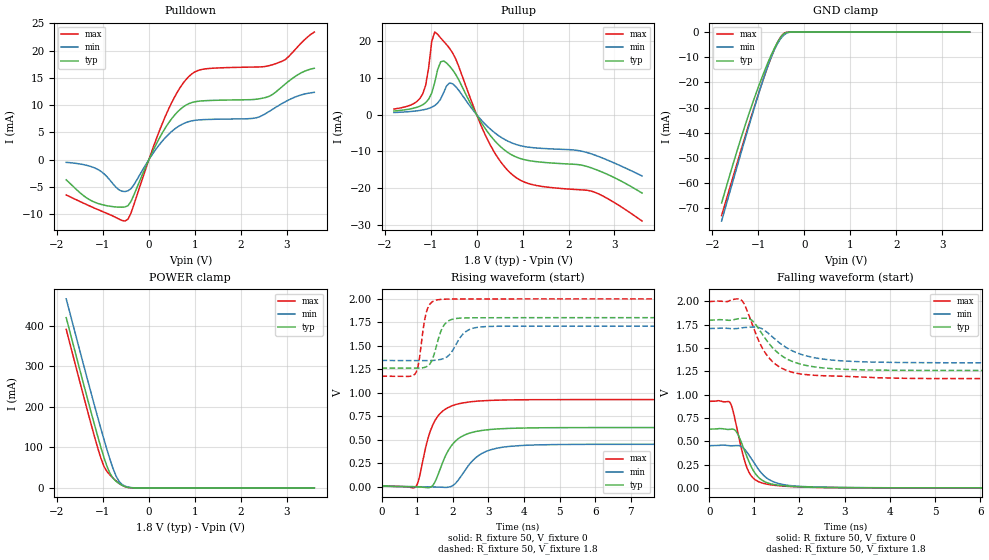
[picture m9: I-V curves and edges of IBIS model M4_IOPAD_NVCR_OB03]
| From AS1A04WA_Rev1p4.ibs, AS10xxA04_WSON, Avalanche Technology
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[Model] M4_IOPAD_NVCR_OB03
Model_type I/O
Enable   Active-High
Vinl  =  0.54
Vinh  =  1.26
Vmeas =  0.9
Cref  =  30e-12
| Capacitance  typ   min   max
C_comp   3.869840e-12   3.575244e-12   4.229518e-12
| Variables   typ   min   max
[GND Clamp Reference]   0   0   0
[POWER Clamp Reference]   1.8   1.71   2
[Pulldown Reference]   0   0   0
[Pullup Reference]   1.8   1.71   2
[Temperature Range]   25   125   -40
[Voltage Range]   1.8   1.71   2
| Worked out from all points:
|   slope of the pulldown table from 0 to 0.27 V, typ, clamps not added: 59.1 ohm
|   slope of the pullup table from 0 to 0.27 V, typ, clamps not added: 51.8 ohm
|   GND clamp passes 1 mA (typ) near -0.46 V on its own axis
|   POWER clamp passes 1 mA (typ) near -0.44 V on its own axis
|   falling waveform, R_fixture 50, V_fixture 0: 20-80 % time 366ps typ, 451ps min, 295ps max; typ from 0.63 V to 0 V
|   falling waveform, R_fixture 50, V_fixture 1.8: 20-80 % time 674ps typ, 798ps min, 550ps max; typ from 1.8 V to 1.26 V
|   rising waveform, R_fixture 50, V_fixture 0: 20-80 % time 546ps typ, 665ps min, 453ps max; typ from 0 V to 0.63 V
|   rising waveform, R_fixture 50, V_fixture 1.8: 20-80 % time 270ps typ, 387ps min, 191ps max; typ from 1.26 V to 1.8 V
[GND Clamp]
| Voltage   I(typ)   I(min)   I(max)
-1.8V     -67.84mA   -74.98mA   -72.81mA
-1.499V   -49.26mA   -55.7mA    -54.28mA
-1.303V   -37.87mA   -43.36mA   -42.4mA
-1.043V   -23.96mA   -27.4mA    -27.1mA
-847.2mV  -14.58mA   -16.27mA   -16.36mA
-716.9mV  -8.973mA   -9.798mA   -9.837mA
-651.7mV  -6.447mA   -7.048mA   -6.896mA
-521.4mV  -2.255mA   -2.801mA   -2.141mA
-456.2mV  -849.3uA   -1.361mA   -679.4uA
-391mV    -172uA     -473.2uA   -88.88uA
-260.7mV  -2.088uA   -22.04uA   -254.3nA
3.6V      0A         0A         0A
[POWER Clamp]
| Voltage   I(typ)   I(min)   I(max)
-1.8V     419.8mA    466.1mA    390.9mA
-1.303V   205.4mA    252.8mA    175.7mA
-1.043V   98.85mA    144.9mA    72.14mA
-977.6mV  74.56mA    119mA      52.56mA
-912.4mV  52.76mA    93.87mA    40.16mA
-847.2mV  35.48mA    69.92mA    31.71mA
-716.9mV  16.42mA    29.44mA    17.31mA
-651.7mV  10.9mA     16.21mA    11.28mA
-586.6mV  6.514mA    8.5mA      6.386mA
-456.2mV  1.168mA    1.854mA    921.1uA
-325.9mV  31.2uA     159.5uA    13.68uA
3.6V      0A         0A         0A
[Pulldown]
| Voltage   I(typ)   I(min)   I(max)
-1.8V     -3.719mA   -509uA     -6.494mA
-1.173V   -7.854mA   -1.556mA   -8.947mA
-651.7mV  -8.731mA   -5.549mA   -10.92mA
-456.2mV  -8.455mA   -5.733mA   -10.94mA
310.3mV   5.166mA    3.582mA    7.006mA
620.7mV   8.732mA    5.967mA    12.41mA
869mV     10.26mA    6.969mA    15.24mA
1.179V    10.78mA    7.325mA    16.58mA
2.283V    11.02mA    7.588mA    16.97mA
2.766V    12.42mA    9.613mA    17.62mA
2.972V    13.9mA     10.63mA    18.37mA
3.6V      16.75mA    12.34mA    23.4mA
[Pullup]
| Voltage   I(typ)   I(min)   I(max)
-1.8V     990uA      579.3uA    1.53mA
-1.173V   2.695mA    1.288mA    5.663mA
-1.108V   3.294mA    1.467mA    8.056mA
-977.6mV  5.876mA    2.022mA    19.91mA
-912.4mV  8.737mA    2.479mA    22.54mA
-782.1mV  14.41mA    4.289mA    20.9mA
-651.7mV  14.06mA    7.877mA    19.08mA
-456.2mV  11mA       7.672mA    15.21mA
248.3mV   -4.86mA    -3.35mA    -7.072mA
744.8mV   -10.83mA   -7.6mA     -16.02mA
2.559V    -14.8mA    -10.96mA   -21.11mA
3.6V      -21.38mA   -16.72mA   -29.01mA
[Ramp]
dV/dt_r   0.377998/0.546255n  0.27146/0.665449n  0.556733/0.452538n
dV/dt_f   0.32444/0.673585n  0.221223/0.798173n  0.497041/0.549934n
R_load = 50
[Falling Waveform]
R_fixture = 50
V_fixture = 0
V_fixture_min = 0
V_fixture_max = 0
| Time   V(typ)   V(min)   V(max)
0s        630mV      452.4mV    927.9mV
458.2ps   627.7mV    451.2mV    917.5mV
516.1ps   630.8mV    451.7mV    847mV
621.6ps   586.2mV    454.2mV    623.8mV
770.2ps   415.7mV    420.7mV    313.3mV
912.3ps   246.8mV    329.8mV    141.6mV
1.176ns   80.2mV     149.1mV    51.62mV
1.538ns   27.86mV    45.97mV    22.68mV
3.447ns   1.138mV    1.798mV    721.8uV
21.88ns   163.6nV    1.016uV    177.4nV
[Falling Waveform]
R_fixture = 50
V_fixture = 1.8
V_fixture_min = 1.71
V_fixture_max = 2
| Time   V(typ)   V(min)   V(max)
0s        1.8V       1.71V      2V
701.2ps   1.819V     1.716V     2.019V
792.2ps   1.821V     1.721V     1.957V
959.5ps   1.792V     1.726V     1.745V
1.151ns   1.668V     1.712V     1.524V
1.334ns   1.543V     1.648V     1.389V
1.742ns   1.378V     1.496V     1.255V
2.229ns   1.306V     1.407V     1.211V
4.342ns   1.261V     1.345V     1.175V
21.88ns   1.259V     1.341V     1.172V
[Rising Waveform]
R_fixture = 50
V_fixture = 0
V_fixture_min = 0
V_fixture_max = 0
| Time   V(typ)   V(min)   V(max)
0s        68.52nV    866.8nV    123.7nV
942.1ps   22.7uV     892.4uV    -6.867mV
1.047ns   -1.804mV   768.2uV    76.76mV
1.326ns   -9.352mV   -644uV     541.1mV
1.511ns   58.2mV     -2.546mV   711.2mV
1.937ns   423.1mV    277.3uV    855.4mV
2.443ns   567.1mV    226.3mV    902mV
3.054ns   609.3mV    392.5mV    919.2mV
4.44ns    627.6mV    446.1mV    927.1mV
21.88ns   630mV      452.4mV    927.9mV
[Rising Waveform]
R_fixture = 50
V_fixture = 1.8
V_fixture_min = 1.71
V_fixture_max = 2
| Time   V(typ)   V(min)   V(max)
0s        1.259V     1.341V     1.172V
948.2ps   1.261V     1.342V     1.203V
1.041ns   1.261V     1.342V     1.311V
1.267ns   1.279V     1.342V     1.867V
1.421ns   1.349V     1.343V     1.967V
1.657ns   1.646V     1.354V     1.994V
1.891ns   1.768V     1.398V     1.998V
2.373ns   1.798V     1.653V     1.999V
2.91ns    1.799V     1.705V     1.999V
21.88ns   1.8V       1.71V      2V
